VERSION 5.7 ;
  NOWIREEXTENSIONATPIN ON ;
  DIVIDERCHAR "/" ;
  BUSBITCHARS "[]" ;
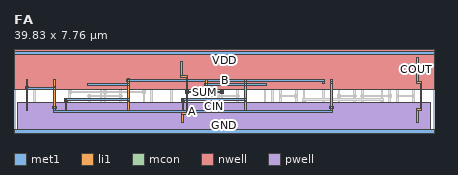
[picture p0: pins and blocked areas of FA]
MACRO FA
  CLASS CORE ;
  FOREIGN FA ;
  ORIGIN 0.000 0.000 ;
  SIZE 39.830 BY 7.760 ;
  SYMMETRY X Y ;
  SITE unitrh ;
  PIN SUM
    DIRECTION OUTPUT ;
    USE SIGNAL ;
    ANTENNADIFFAREA 1.543800 ;
    PORT
      LAYER met1 ;
        RECT 16.285 3.965 16.515 3.995 ;
        RECT 19.615 3.965 19.845 3.995 ;
        RECT 16.255 3.795 19.875 3.965 ;
        RECT 16.285 3.765 16.515 3.795 ;
        RECT 19.615 3.765 19.845 3.795 ;
    END
    PORT
      LAYER li1 ;
        RECT 15.835 5.470 16.005 6.740 ;
        RECT 15.835 5.300 16.485 5.470 ;
        RECT 16.315 1.920 16.485 5.300 ;
        RECT 15.875 1.750 16.485 1.920 ;
        RECT 15.875 1.020 16.045 1.750 ;
      LAYER mcon ;
        RECT 16.315 3.795 16.485 3.965 ;
    END
  END SUM
  PIN COUT
    DIRECTION OUTPUT ;
    USE SIGNAL ;
    ANTENNADIFFAREA 0.771900 ;
    PORT
      LAYER li1 ;
        RECT 38.150 4.845 38.320 7.200 ;
        RECT 38.150 4.675 38.685 4.845 ;
        RECT 38.515 2.345 38.685 4.675 ;
        RECT 38.145 2.175 38.685 2.345 ;
        RECT 38.145 1.020 38.315 2.175 ;
    END
  END COUT
  PIN A
    DIRECTION INPUT ;
    USE SIGNAL ;
    ANTENNAGATEAREA 3.087750 ;
    PORT
      LAYER met1 ;
        RECT 1.115 4.335 1.345 4.365 ;
        RECT 3.705 4.335 3.935 4.365 ;
        RECT 1.085 4.165 3.965 4.335 ;
        RECT 1.115 4.135 1.345 4.165 ;
        RECT 3.705 4.135 3.935 4.165 ;
        RECT 3.735 2.515 3.905 2.545 ;
        RECT 30.005 2.515 30.175 2.545 ;
        RECT 3.705 2.285 3.935 2.515 ;
        RECT 29.975 2.285 30.205 2.515 ;
        RECT 3.735 2.115 3.905 2.285 ;
        RECT 30.005 2.115 30.175 2.285 ;
        RECT 3.735 1.945 30.175 2.115 ;
    END
    PORT
      LAYER li1 ;
        RECT 3.735 2.485 3.905 5.045 ;
        RECT 3.655 2.315 3.985 2.485 ;
        RECT 3.735 2.100 3.905 2.315 ;
      LAYER mcon ;
        RECT 3.735 4.165 3.905 4.335 ;
        RECT 3.735 2.315 3.905 2.485 ;
    END
    PORT
      LAYER li1 ;
        RECT 30.035 4.890 30.205 5.045 ;
        RECT 30.005 4.715 30.205 4.890 ;
        RECT 30.005 2.485 30.175 4.715 ;
        RECT 29.925 2.315 30.255 2.485 ;
        RECT 30.005 2.095 30.175 2.315 ;
      LAYER mcon ;
        RECT 30.005 2.315 30.175 2.485 ;
    END
    PORT
      LAYER li1 ;
        RECT 1.145 2.100 1.315 5.045 ;
      LAYER mcon ;
        RECT 1.145 4.165 1.315 4.335 ;
    END
  END A
  PIN B
    DIRECTION INPUT ;
    USE SIGNAL ;
    ANTENNAGATEAREA 3.087750 ;
    PORT
      LAYER met1 ;
        RECT 10.735 5.075 10.965 5.105 ;
        RECT 10.705 4.925 29.435 5.075 ;
        RECT 10.705 4.905 29.465 4.925 ;
        RECT 10.735 4.875 10.965 4.905 ;
        RECT 7.035 4.705 7.265 4.735 ;
        RECT 10.735 4.705 10.965 4.735 ;
        RECT 7.005 4.535 10.995 4.705 ;
        RECT 29.235 4.695 29.465 4.905 ;
        RECT 29.265 4.665 29.435 4.695 ;
        RECT 7.035 4.505 7.265 4.535 ;
        RECT 10.735 4.505 10.965 4.535 ;
        RECT 4.815 3.225 5.045 3.255 ;
        RECT 10.735 3.225 10.965 3.255 ;
        RECT 4.785 3.055 10.995 3.225 ;
        RECT 4.815 3.025 5.045 3.055 ;
        RECT 10.735 3.025 10.965 3.055 ;
    END
    PORT
      LAYER li1 ;
        RECT 10.765 2.100 10.935 5.155 ;
      LAYER mcon ;
        RECT 10.765 4.905 10.935 5.075 ;
        RECT 10.765 4.535 10.935 4.705 ;
        RECT 10.765 3.055 10.935 3.225 ;
    END
    PORT
      LAYER li1 ;
        RECT 4.845 2.100 5.015 3.305 ;
      LAYER mcon ;
        RECT 4.845 3.055 5.015 3.225 ;
    END
  END B
  PIN CIN
    DIRECTION INPUT ;
    USE SIGNAL ;
    ANTENNAGATEAREA 3.087750 ;
    PORT
      LAYER met1 ;
        RECT 18.135 4.705 18.365 4.735 ;
        RECT 21.835 4.705 22.065 4.735 ;
        RECT 23.685 4.705 23.915 4.735 ;
        RECT 18.105 4.535 23.945 4.705 ;
        RECT 18.135 4.505 18.365 4.535 ;
        RECT 21.835 4.505 22.065 4.535 ;
        RECT 23.685 4.505 23.915 4.535 ;
        RECT 15.915 3.225 16.145 3.255 ;
        RECT 21.835 3.225 22.065 3.255 ;
        RECT 15.885 3.055 22.095 3.225 ;
        RECT 15.915 3.025 16.145 3.055 ;
        RECT 21.835 3.025 22.065 3.055 ;
    END
    PORT
      LAYER li1 ;
        RECT 21.865 2.100 22.035 5.045 ;
      LAYER mcon ;
        RECT 21.865 4.535 22.035 4.705 ;
        RECT 21.865 3.055 22.035 3.225 ;
    END
    PORT
      LAYER li1 ;
        RECT 18.165 4.455 18.335 5.045 ;
      LAYER mcon ;
        RECT 18.165 4.535 18.335 4.705 ;
    END
    PORT
      LAYER li1 ;
        RECT 15.945 2.100 16.115 3.305 ;
      LAYER mcon ;
        RECT 15.945 3.055 16.115 3.225 ;
    END
  END CIN
  PIN VDD
    DIRECTION INOUT ;
    USE POWER ;
    SHAPE ABUTMENT ;
    PORT
      LAYER nwell ;
        RECT 0.000 4.110 39.830 7.940 ;
      LAYER met1 ;
        RECT 0.000 7.410 39.830 7.760 ;
    END
  END VDD
  PIN GND
    DIRECTION INOUT ;
    USE GROUND ;
    SHAPE ABUTMENT ;
    PORT
      LAYER pwell ;
        RECT 0.320 0.000 39.510 2.900 ;
      LAYER met1 ;
        RECT 0.000 0.000 39.830 0.350 ;
    END
  END GND
  OBS
      LAYER li1 ;
        RECT 0.000 7.410 39.830 7.760 ;
        RECT 0.320 4.290 0.660 7.410 ;
        RECT 1.080 5.365 1.250 7.410 ;
        RECT 1.520 4.845 1.690 7.200 ;
        RECT 1.960 5.365 2.130 7.410 ;
        RECT 1.520 4.675 2.055 4.845 ;
        RECT 0.320 0.350 0.660 2.900 ;
        RECT 1.885 2.345 2.055 4.675 ;
        RECT 2.540 4.290 2.880 7.410 ;
        RECT 3.415 5.470 3.585 7.080 ;
        RECT 3.855 5.730 4.025 7.410 ;
        RECT 4.295 7.000 5.345 7.170 ;
        RECT 4.295 5.470 4.465 7.000 ;
        RECT 3.415 5.300 4.465 5.470 ;
        RECT 4.735 5.470 4.905 6.740 ;
        RECT 5.175 5.730 5.345 7.000 ;
        RECT 4.735 5.300 5.385 5.470 ;
        RECT 4.845 4.085 5.015 5.045 ;
        RECT 1.515 2.175 2.055 2.345 ;
        RECT 1.035 0.800 1.205 1.930 ;
        RECT 1.515 1.020 1.685 2.175 ;
        RECT 2.005 0.800 2.175 1.930 ;
        RECT 1.035 0.630 2.175 0.800 ;
        RECT 1.035 0.350 1.205 0.630 ;
        RECT 1.520 0.350 1.690 0.630 ;
        RECT 2.005 0.350 2.175 0.630 ;
        RECT 2.540 0.350 2.880 2.900 ;
        RECT 3.320 1.850 3.490 1.930 ;
        RECT 4.290 1.850 4.460 1.930 ;
        RECT 5.215 1.920 5.385 5.300 ;
        RECT 5.870 4.290 6.210 7.410 ;
        RECT 6.745 5.470 6.915 7.080 ;
        RECT 7.185 5.730 7.355 7.410 ;
        RECT 7.625 7.000 8.675 7.170 ;
        RECT 7.625 5.470 7.795 7.000 ;
        RECT 6.745 5.300 7.795 5.470 ;
        RECT 8.065 5.470 8.235 6.740 ;
        RECT 8.505 5.730 8.675 7.000 ;
        RECT 8.065 5.300 8.715 5.470 ;
        RECT 7.065 4.455 7.235 5.045 ;
        RECT 3.320 1.680 4.460 1.850 ;
        RECT 3.320 0.550 3.490 1.680 ;
        RECT 3.805 0.350 3.975 1.305 ;
        RECT 4.290 0.800 4.460 1.680 ;
        RECT 4.775 1.750 5.385 1.920 ;
        RECT 4.775 1.020 4.945 1.750 ;
        RECT 5.260 0.800 5.430 1.570 ;
        RECT 4.290 0.630 5.430 0.800 ;
        RECT 4.290 0.550 4.460 0.630 ;
        RECT 5.260 0.550 5.430 0.630 ;
        RECT 5.870 0.350 6.210 2.900 ;
        RECT 7.065 2.100 7.235 3.675 ;
        RECT 8.175 2.100 8.345 5.045 ;
        RECT 6.650 1.850 6.820 1.930 ;
        RECT 7.620 1.850 7.790 1.930 ;
        RECT 8.545 1.920 8.715 5.300 ;
        RECT 9.200 4.290 9.540 7.410 ;
        RECT 9.950 5.365 10.120 7.410 ;
        RECT 10.390 4.845 10.560 7.200 ;
        RECT 10.830 5.365 11.000 7.410 ;
        RECT 10.025 4.675 10.560 4.845 ;
        RECT 6.650 1.680 7.790 1.850 ;
        RECT 6.650 0.550 6.820 1.680 ;
        RECT 7.135 0.350 7.305 1.305 ;
        RECT 7.620 0.800 7.790 1.680 ;
        RECT 8.105 1.750 8.715 1.920 ;
        RECT 8.105 1.020 8.275 1.750 ;
        RECT 8.590 0.800 8.760 1.570 ;
        RECT 7.620 0.630 8.760 0.800 ;
        RECT 7.620 0.550 7.790 0.630 ;
        RECT 8.590 0.550 8.760 0.630 ;
        RECT 9.200 0.350 9.540 2.900 ;
        RECT 10.025 2.345 10.195 4.675 ;
        RECT 11.420 4.290 11.760 7.410 ;
        RECT 12.180 5.365 12.350 7.410 ;
        RECT 10.025 2.175 10.565 2.345 ;
        RECT 9.905 0.800 10.075 1.930 ;
        RECT 10.395 1.020 10.565 2.175 ;
        RECT 10.875 0.800 11.045 1.930 ;
        RECT 9.905 0.630 11.045 0.800 ;
        RECT 9.905 0.350 10.075 0.630 ;
        RECT 10.390 0.350 10.560 0.630 ;
        RECT 10.875 0.350 11.045 0.630 ;
        RECT 11.420 0.350 11.760 2.900 ;
        RECT 12.245 2.100 12.415 5.045 ;
        RECT 12.620 4.845 12.790 7.200 ;
        RECT 13.060 5.365 13.230 7.410 ;
        RECT 12.620 4.675 13.155 4.845 ;
        RECT 12.985 2.345 13.155 4.675 ;
        RECT 13.640 4.290 13.980 7.410 ;
        RECT 14.515 5.470 14.685 7.080 ;
        RECT 14.955 5.730 15.125 7.410 ;
        RECT 15.395 7.000 16.445 7.170 ;
        RECT 15.395 5.470 15.565 7.000 ;
        RECT 16.275 5.730 16.445 7.000 ;
        RECT 14.515 5.300 15.565 5.470 ;
        RECT 12.615 2.175 13.155 2.345 ;
        RECT 12.135 0.800 12.305 1.930 ;
        RECT 12.615 1.020 12.785 2.175 ;
        RECT 13.105 0.800 13.275 1.930 ;
        RECT 12.135 0.630 13.275 0.800 ;
        RECT 12.135 0.350 12.305 0.630 ;
        RECT 12.620 0.350 12.790 0.630 ;
        RECT 13.105 0.350 13.275 0.630 ;
        RECT 13.640 0.350 13.980 2.900 ;
        RECT 14.835 2.100 15.005 5.045 ;
        RECT 15.945 4.085 16.115 5.045 ;
        RECT 16.970 4.290 17.310 7.410 ;
        RECT 17.845 5.470 18.015 7.080 ;
        RECT 18.285 5.730 18.455 7.410 ;
        RECT 18.725 7.000 19.775 7.170 ;
        RECT 18.725 5.470 18.895 7.000 ;
        RECT 17.845 5.300 18.895 5.470 ;
        RECT 19.165 5.470 19.335 6.740 ;
        RECT 19.605 5.730 19.775 7.000 ;
        RECT 19.165 5.300 19.815 5.470 ;
        RECT 14.420 1.850 14.590 1.930 ;
        RECT 15.390 1.850 15.560 1.930 ;
        RECT 14.420 1.680 15.560 1.850 ;
        RECT 14.420 0.550 14.590 1.680 ;
        RECT 14.905 0.350 15.075 1.305 ;
        RECT 15.390 0.800 15.560 1.680 ;
        RECT 16.360 0.800 16.530 1.570 ;
        RECT 15.390 0.630 16.530 0.800 ;
        RECT 15.390 0.550 15.560 0.630 ;
        RECT 16.360 0.550 16.530 0.630 ;
        RECT 16.970 0.350 17.310 2.900 ;
        RECT 18.165 2.100 18.335 3.675 ;
        RECT 19.275 2.100 19.445 5.045 ;
        RECT 17.750 1.850 17.920 1.930 ;
        RECT 18.720 1.850 18.890 1.930 ;
        RECT 19.645 1.920 19.815 5.300 ;
        RECT 20.300 4.290 20.640 7.410 ;
        RECT 21.050 5.365 21.220 7.410 ;
        RECT 21.490 4.845 21.660 7.200 ;
        RECT 21.930 5.365 22.100 7.410 ;
        RECT 21.125 4.675 21.660 4.845 ;
        RECT 17.750 1.680 18.890 1.850 ;
        RECT 17.750 0.550 17.920 1.680 ;
        RECT 18.235 0.350 18.405 1.305 ;
        RECT 18.720 0.800 18.890 1.680 ;
        RECT 19.205 1.750 19.815 1.920 ;
        RECT 19.205 1.020 19.375 1.750 ;
        RECT 19.690 0.800 19.860 1.570 ;
        RECT 18.720 0.630 19.860 0.800 ;
        RECT 18.720 0.550 18.890 0.630 ;
        RECT 19.690 0.550 19.860 0.630 ;
        RECT 20.300 0.350 20.640 2.900 ;
        RECT 21.125 2.345 21.295 4.675 ;
        RECT 22.520 4.290 22.860 7.410 ;
        RECT 23.395 5.315 23.565 7.410 ;
        RECT 23.835 5.465 24.005 7.200 ;
        RECT 24.275 5.735 24.445 7.410 ;
        RECT 24.715 5.465 24.885 7.200 ;
        RECT 25.155 5.735 25.325 7.410 ;
        RECT 23.835 5.295 25.365 5.465 ;
        RECT 21.125 2.175 21.665 2.345 ;
        RECT 21.005 0.800 21.175 1.930 ;
        RECT 21.495 1.020 21.665 2.175 ;
        RECT 21.975 0.800 22.145 1.930 ;
        RECT 21.005 0.630 22.145 0.800 ;
        RECT 21.005 0.350 21.175 0.630 ;
        RECT 21.490 0.350 21.660 0.630 ;
        RECT 21.975 0.350 22.145 0.630 ;
        RECT 22.520 0.350 22.860 2.900 ;
        RECT 23.715 2.095 23.885 5.045 ;
        RECT 24.485 4.890 24.655 5.045 ;
        RECT 24.455 4.715 24.655 4.890 ;
        RECT 24.455 2.095 24.625 4.715 ;
        RECT 23.300 1.845 23.470 1.925 ;
        RECT 24.270 1.845 24.440 1.925 ;
        RECT 25.195 1.920 25.365 5.295 ;
        RECT 25.850 4.290 26.190 7.410 ;
        RECT 26.610 5.365 26.780 7.410 ;
        RECT 23.300 1.675 24.440 1.845 ;
        RECT 23.300 0.545 23.470 1.675 ;
        RECT 23.785 0.350 23.955 1.300 ;
        RECT 24.270 0.795 24.440 1.675 ;
        RECT 24.755 1.750 25.365 1.920 ;
        RECT 24.755 1.015 24.925 1.750 ;
        RECT 25.240 0.795 25.410 1.565 ;
        RECT 24.270 0.625 25.410 0.795 ;
        RECT 24.270 0.545 24.440 0.625 ;
        RECT 25.240 0.545 25.410 0.625 ;
        RECT 25.850 0.350 26.190 2.900 ;
        RECT 26.675 2.100 26.845 5.045 ;
        RECT 27.050 4.845 27.220 7.200 ;
        RECT 27.490 5.365 27.660 7.410 ;
        RECT 27.050 4.675 27.585 4.845 ;
        RECT 27.415 2.345 27.585 4.675 ;
        RECT 28.070 4.290 28.410 7.410 ;
        RECT 28.945 5.315 29.115 7.410 ;
        RECT 29.385 5.465 29.555 7.200 ;
        RECT 29.825 5.735 29.995 7.410 ;
        RECT 30.265 5.465 30.435 7.200 ;
        RECT 30.705 5.735 30.875 7.410 ;
        RECT 29.385 5.295 30.915 5.465 ;
        RECT 29.265 4.895 29.435 5.075 ;
        RECT 29.185 4.725 29.515 4.895 ;
        RECT 27.045 2.175 27.585 2.345 ;
        RECT 26.565 0.800 26.735 1.930 ;
        RECT 27.045 1.020 27.215 2.175 ;
        RECT 27.535 0.800 27.705 1.930 ;
        RECT 26.565 0.630 27.705 0.800 ;
        RECT 26.565 0.350 26.735 0.630 ;
        RECT 27.050 0.350 27.220 0.630 ;
        RECT 27.535 0.350 27.705 0.630 ;
        RECT 28.070 0.350 28.410 2.900 ;
        RECT 29.265 2.095 29.435 4.725 ;
        RECT 28.850 1.845 29.020 1.925 ;
        RECT 29.820 1.845 29.990 1.925 ;
        RECT 30.745 1.920 30.915 5.295 ;
        RECT 31.400 4.290 31.740 7.410 ;
        RECT 32.160 5.365 32.330 7.410 ;
        RECT 28.850 1.675 29.990 1.845 ;
        RECT 28.850 0.545 29.020 1.675 ;
        RECT 29.335 0.350 29.505 1.300 ;
        RECT 29.820 0.795 29.990 1.675 ;
        RECT 30.305 1.750 30.915 1.920 ;
        RECT 30.305 1.015 30.475 1.750 ;
        RECT 30.790 0.795 30.960 1.565 ;
        RECT 29.820 0.625 30.960 0.795 ;
        RECT 29.820 0.545 29.990 0.625 ;
        RECT 30.790 0.545 30.960 0.625 ;
        RECT 31.400 0.350 31.740 2.900 ;
        RECT 32.225 2.100 32.395 5.045 ;
        RECT 32.600 4.845 32.770 7.200 ;
        RECT 33.040 5.365 33.210 7.410 ;
        RECT 32.600 4.675 33.135 4.845 ;
        RECT 32.965 2.345 33.135 4.675 ;
        RECT 33.620 4.290 33.960 7.410 ;
        RECT 34.495 5.475 34.665 7.205 ;
        RECT 34.935 5.735 35.105 7.410 ;
        RECT 35.375 7.005 36.425 7.175 ;
        RECT 35.375 5.475 35.545 7.005 ;
        RECT 34.495 5.305 35.545 5.475 ;
        RECT 35.815 5.475 35.985 6.745 ;
        RECT 36.255 5.735 36.425 7.005 ;
        RECT 35.815 5.305 36.465 5.475 ;
        RECT 34.660 4.890 34.830 5.050 ;
        RECT 35.590 4.890 35.760 5.050 ;
        RECT 34.660 4.720 34.985 4.890 ;
        RECT 32.595 2.175 33.135 2.345 ;
        RECT 32.115 0.800 32.285 1.930 ;
        RECT 32.595 1.020 32.765 2.175 ;
        RECT 33.085 0.800 33.255 1.930 ;
        RECT 32.115 0.630 33.255 0.800 ;
        RECT 32.115 0.350 32.285 0.630 ;
        RECT 32.600 0.350 32.770 0.630 ;
        RECT 33.085 0.350 33.255 0.630 ;
        RECT 33.620 0.350 33.960 2.900 ;
        RECT 34.815 2.095 34.985 4.720 ;
        RECT 35.555 4.720 35.760 4.890 ;
        RECT 35.555 2.095 35.725 4.720 ;
        RECT 34.400 0.795 34.570 1.925 ;
        RECT 36.295 1.920 36.465 5.305 ;
        RECT 36.950 4.290 37.290 7.410 ;
        RECT 37.710 5.365 37.880 7.410 ;
        RECT 38.590 5.365 38.760 7.410 ;
        RECT 34.885 1.750 36.465 1.920 ;
        RECT 34.885 1.015 35.055 1.750 ;
        RECT 35.370 0.795 35.540 1.570 ;
        RECT 35.855 1.015 36.025 1.750 ;
        RECT 36.340 0.795 36.510 1.570 ;
        RECT 34.400 0.625 36.510 0.795 ;
        RECT 34.400 0.350 34.570 0.625 ;
        RECT 34.885 0.350 35.055 0.625 ;
        RECT 35.370 0.350 35.540 0.625 ;
        RECT 35.855 0.350 36.025 0.625 ;
        RECT 36.340 0.350 36.510 0.625 ;
        RECT 36.950 0.350 37.290 2.900 ;
        RECT 37.775 2.100 37.945 5.045 ;
        RECT 39.170 4.290 39.510 7.410 ;
        RECT 37.665 0.800 37.835 1.930 ;
        RECT 38.635 0.800 38.805 1.930 ;
        RECT 37.665 0.630 38.805 0.800 ;
        RECT 37.665 0.350 37.835 0.630 ;
        RECT 38.150 0.350 38.320 0.630 ;
        RECT 38.635 0.350 38.805 0.630 ;
        RECT 39.170 0.350 39.510 2.900 ;
        RECT 0.000 0.000 39.830 0.350 ;
      LAYER mcon ;
        RECT 0.775 7.495 0.945 7.665 ;
        RECT 1.145 7.495 1.315 7.665 ;
        RECT 1.515 7.495 1.685 7.665 ;
        RECT 1.885 7.495 2.055 7.665 ;
        RECT 2.255 7.495 2.425 7.665 ;
        RECT 2.995 7.495 3.165 7.665 ;
        RECT 3.365 7.495 3.535 7.665 ;
        RECT 3.735 7.495 3.905 7.665 ;
        RECT 4.105 7.495 4.275 7.665 ;
        RECT 4.475 7.495 4.645 7.665 ;
        RECT 4.845 7.495 5.015 7.665 ;
        RECT 5.215 7.495 5.385 7.665 ;
        RECT 5.585 7.495 5.755 7.665 ;
        RECT 6.325 7.495 6.495 7.665 ;
        RECT 6.695 7.495 6.865 7.665 ;
        RECT 7.065 7.495 7.235 7.665 ;
        RECT 7.435 7.495 7.605 7.665 ;
        RECT 7.805 7.495 7.975 7.665 ;
        RECT 8.175 7.495 8.345 7.665 ;
        RECT 8.545 7.495 8.715 7.665 ;
        RECT 8.915 7.495 9.085 7.665 ;
        RECT 9.655 7.495 9.825 7.665 ;
        RECT 10.025 7.495 10.195 7.665 ;
        RECT 10.395 7.495 10.565 7.665 ;
        RECT 10.765 7.495 10.935 7.665 ;
        RECT 11.135 7.495 11.305 7.665 ;
        RECT 11.875 7.495 12.045 7.665 ;
        RECT 12.245 7.495 12.415 7.665 ;
        RECT 12.615 7.495 12.785 7.665 ;
        RECT 12.985 7.495 13.155 7.665 ;
        RECT 13.355 7.495 13.525 7.665 ;
        RECT 14.095 7.495 14.265 7.665 ;
        RECT 14.465 7.495 14.635 7.665 ;
        RECT 14.835 7.495 15.005 7.665 ;
        RECT 15.205 7.495 15.375 7.665 ;
        RECT 15.575 7.495 15.745 7.665 ;
        RECT 15.945 7.495 16.115 7.665 ;
        RECT 16.315 7.495 16.485 7.665 ;
        RECT 16.685 7.495 16.855 7.665 ;
        RECT 17.425 7.495 17.595 7.665 ;
        RECT 17.795 7.495 17.965 7.665 ;
        RECT 18.165 7.495 18.335 7.665 ;
        RECT 18.535 7.495 18.705 7.665 ;
        RECT 18.905 7.495 19.075 7.665 ;
        RECT 19.275 7.495 19.445 7.665 ;
        RECT 19.645 7.495 19.815 7.665 ;
        RECT 20.015 7.495 20.185 7.665 ;
        RECT 20.755 7.495 20.925 7.665 ;
        RECT 21.125 7.495 21.295 7.665 ;
        RECT 21.495 7.495 21.665 7.665 ;
        RECT 21.865 7.495 22.035 7.665 ;
        RECT 22.235 7.495 22.405 7.665 ;
        RECT 22.975 7.495 23.145 7.665 ;
        RECT 23.345 7.495 23.515 7.665 ;
        RECT 23.715 7.495 23.885 7.665 ;
        RECT 24.085 7.495 24.255 7.665 ;
        RECT 24.455 7.495 24.625 7.665 ;
        RECT 24.825 7.495 24.995 7.665 ;
        RECT 25.195 7.495 25.365 7.665 ;
        RECT 25.565 7.495 25.735 7.665 ;
        RECT 26.305 7.495 26.475 7.665 ;
        RECT 26.675 7.495 26.845 7.665 ;
        RECT 27.045 7.495 27.215 7.665 ;
        RECT 27.415 7.495 27.585 7.665 ;
        RECT 27.785 7.495 27.955 7.665 ;
        RECT 28.525 7.495 28.695 7.665 ;
        RECT 28.895 7.495 29.065 7.665 ;
        RECT 29.265 7.495 29.435 7.665 ;
        RECT 29.635 7.495 29.805 7.665 ;
        RECT 30.005 7.495 30.175 7.665 ;
        RECT 30.375 7.495 30.545 7.665 ;
        RECT 30.745 7.495 30.915 7.665 ;
        RECT 31.115 7.495 31.285 7.665 ;
        RECT 31.855 7.495 32.025 7.665 ;
        RECT 32.225 7.495 32.395 7.665 ;
        RECT 32.595 7.495 32.765 7.665 ;
        RECT 32.965 7.495 33.135 7.665 ;
        RECT 33.335 7.495 33.505 7.665 ;
        RECT 34.075 7.495 34.245 7.665 ;
        RECT 34.445 7.495 34.615 7.665 ;
        RECT 34.815 7.495 34.985 7.665 ;
        RECT 35.185 7.495 35.355 7.665 ;
        RECT 35.555 7.495 35.725 7.665 ;
        RECT 35.925 7.495 36.095 7.665 ;
        RECT 36.295 7.495 36.465 7.665 ;
        RECT 36.665 7.495 36.835 7.665 ;
        RECT 37.405 7.495 37.575 7.665 ;
        RECT 37.775 7.495 37.945 7.665 ;
        RECT 38.145 7.495 38.315 7.665 ;
        RECT 38.515 7.495 38.685 7.665 ;
        RECT 38.885 7.495 39.055 7.665 ;
        RECT 4.845 4.165 5.015 4.335 ;
        RECT 7.065 4.535 7.235 4.705 ;
        RECT 5.215 3.795 5.385 3.965 ;
        RECT 1.885 2.685 2.055 2.855 ;
        RECT 7.065 3.425 7.235 3.595 ;
        RECT 8.175 2.685 8.345 2.855 ;
        RECT 8.545 3.795 8.715 3.965 ;
        RECT 10.025 4.165 10.195 4.335 ;
        RECT 10.025 3.425 10.195 3.595 ;
        RECT 12.245 4.165 12.415 4.335 ;
        RECT 12.245 3.795 12.415 3.965 ;
        RECT 12.245 2.315 12.415 2.485 ;
        RECT 14.835 4.165 15.005 4.335 ;
        RECT 12.985 2.685 13.155 2.855 ;
        RECT 15.945 4.165 16.115 4.335 ;
        RECT 18.165 3.425 18.335 3.595 ;
        RECT 19.275 2.685 19.445 2.855 ;
        RECT 19.645 3.795 19.815 3.965 ;
        RECT 21.125 4.165 21.295 4.335 ;
        RECT 23.715 4.535 23.885 4.705 ;
        RECT 21.125 3.425 21.295 3.595 ;
        RECT 24.455 2.315 24.625 2.485 ;
        RECT 25.195 3.425 25.365 3.595 ;
        RECT 26.675 3.425 26.845 3.595 ;
        RECT 29.265 4.725 29.435 4.895 ;
        RECT 27.415 3.055 27.585 3.225 ;
        RECT 30.745 3.425 30.915 3.595 ;
        RECT 32.225 3.425 32.395 3.595 ;
        RECT 32.965 3.425 33.135 3.595 ;
        RECT 34.815 3.055 34.985 3.225 ;
        RECT 35.555 3.425 35.725 3.595 ;
        RECT 36.295 3.425 36.465 3.595 ;
        RECT 37.775 3.425 37.945 3.595 ;
        RECT 0.775 0.095 0.945 0.265 ;
        RECT 1.145 0.095 1.315 0.265 ;
        RECT 1.515 0.095 1.685 0.265 ;
        RECT 1.885 0.095 2.055 0.265 ;
        RECT 2.255 0.095 2.425 0.265 ;
        RECT 2.995 0.095 3.165 0.265 ;
        RECT 3.365 0.095 3.535 0.265 ;
        RECT 3.735 0.095 3.905 0.265 ;
        RECT 4.105 0.095 4.275 0.265 ;
        RECT 4.475 0.095 4.645 0.265 ;
        RECT 4.845 0.095 5.015 0.265 ;
        RECT 5.215 0.095 5.385 0.265 ;
        RECT 5.585 0.095 5.755 0.265 ;
        RECT 6.325 0.095 6.495 0.265 ;
        RECT 6.695 0.095 6.865 0.265 ;
        RECT 7.065 0.095 7.235 0.265 ;
        RECT 7.435 0.095 7.605 0.265 ;
        RECT 7.805 0.095 7.975 0.265 ;
        RECT 8.175 0.095 8.345 0.265 ;
        RECT 8.545 0.095 8.715 0.265 ;
        RECT 8.915 0.095 9.085 0.265 ;
        RECT 9.655 0.095 9.825 0.265 ;
        RECT 10.025 0.095 10.195 0.265 ;
        RECT 10.395 0.095 10.565 0.265 ;
        RECT 10.765 0.095 10.935 0.265 ;
        RECT 11.135 0.095 11.305 0.265 ;
        RECT 11.875 0.095 12.045 0.265 ;
        RECT 12.245 0.095 12.415 0.265 ;
        RECT 12.615 0.095 12.785 0.265 ;
        RECT 12.985 0.095 13.155 0.265 ;
        RECT 13.355 0.095 13.525 0.265 ;
        RECT 14.095 0.095 14.265 0.265 ;
        RECT 14.465 0.095 14.635 0.265 ;
        RECT 14.835 0.095 15.005 0.265 ;
        RECT 15.205 0.095 15.375 0.265 ;
        RECT 15.575 0.095 15.745 0.265 ;
        RECT 15.945 0.095 16.115 0.265 ;
        RECT 16.315 0.095 16.485 0.265 ;
        RECT 16.685 0.095 16.855 0.265 ;
        RECT 17.425 0.095 17.595 0.265 ;
        RECT 17.795 0.095 17.965 0.265 ;
        RECT 18.165 0.095 18.335 0.265 ;
        RECT 18.535 0.095 18.705 0.265 ;
        RECT 18.905 0.095 19.075 0.265 ;
        RECT 19.275 0.095 19.445 0.265 ;
        RECT 19.645 0.095 19.815 0.265 ;
        RECT 20.015 0.095 20.185 0.265 ;
        RECT 20.755 0.095 20.925 0.265 ;
        RECT 21.125 0.095 21.295 0.265 ;
        RECT 21.495 0.095 21.665 0.265 ;
        RECT 21.865 0.095 22.035 0.265 ;
        RECT 22.235 0.095 22.405 0.265 ;
        RECT 22.975 0.095 23.145 0.265 ;
        RECT 23.345 0.095 23.515 0.265 ;
        RECT 23.715 0.095 23.885 0.265 ;
        RECT 24.085 0.095 24.255 0.265 ;
        RECT 24.455 0.095 24.625 0.265 ;
        RECT 24.825 0.095 24.995 0.265 ;
        RECT 25.195 0.095 25.365 0.265 ;
        RECT 25.565 0.095 25.735 0.265 ;
        RECT 26.305 0.095 26.475 0.265 ;
        RECT 26.675 0.095 26.845 0.265 ;
        RECT 27.045 0.095 27.215 0.265 ;
        RECT 27.415 0.095 27.585 0.265 ;
        RECT 27.785 0.095 27.955 0.265 ;
        RECT 28.525 0.095 28.695 0.265 ;
        RECT 28.895 0.095 29.065 0.265 ;
        RECT 29.265 0.095 29.435 0.265 ;
        RECT 29.635 0.095 29.805 0.265 ;
        RECT 30.005 0.095 30.175 0.265 ;
        RECT 30.375 0.095 30.545 0.265 ;
        RECT 30.745 0.095 30.915 0.265 ;
        RECT 31.115 0.095 31.285 0.265 ;
        RECT 31.855 0.095 32.025 0.265 ;
        RECT 32.225 0.095 32.395 0.265 ;
        RECT 32.595 0.095 32.765 0.265 ;
        RECT 32.965 0.095 33.135 0.265 ;
        RECT 33.335 0.095 33.505 0.265 ;
        RECT 34.075 0.095 34.245 0.265 ;
        RECT 34.445 0.095 34.615 0.265 ;
        RECT 34.815 0.095 34.985 0.265 ;
        RECT 35.185 0.095 35.355 0.265 ;
        RECT 35.555 0.095 35.725 0.265 ;
        RECT 35.925 0.095 36.095 0.265 ;
        RECT 36.295 0.095 36.465 0.265 ;
        RECT 36.665 0.095 36.835 0.265 ;
        RECT 37.405 0.095 37.575 0.265 ;
        RECT 37.775 0.095 37.945 0.265 ;
        RECT 38.145 0.095 38.315 0.265 ;
        RECT 38.515 0.095 38.685 0.265 ;
        RECT 38.885 0.095 39.055 0.265 ;
      LAYER met1 ;
        RECT 4.815 4.335 5.045 4.365 ;
        RECT 9.995 4.335 10.225 4.365 ;
        RECT 12.215 4.335 12.445 4.365 ;
        RECT 14.805 4.335 15.035 4.365 ;
        RECT 15.915 4.335 16.145 4.365 ;
        RECT 21.095 4.335 21.325 4.365 ;
        RECT 4.785 4.165 10.255 4.335 ;
        RECT 12.185 4.165 15.065 4.335 ;
        RECT 15.885 4.165 21.355 4.335 ;
        RECT 4.815 4.135 5.045 4.165 ;
        RECT 9.995 4.135 10.225 4.165 ;
        RECT 12.215 4.135 12.445 4.165 ;
        RECT 14.805 4.135 15.035 4.165 ;
        RECT 15.915 4.135 16.145 4.165 ;
        RECT 21.095 4.135 21.325 4.165 ;
        RECT 5.185 3.965 5.415 3.995 ;
        RECT 8.515 3.965 8.745 3.995 ;
        RECT 12.215 3.965 12.445 3.995 ;
        RECT 5.155 3.795 12.475 3.965 ;
        RECT 5.185 3.765 5.415 3.795 ;
        RECT 8.515 3.765 8.745 3.795 ;
        RECT 12.215 3.765 12.445 3.795 ;
        RECT 7.035 3.595 7.265 3.625 ;
        RECT 9.995 3.595 10.225 3.625 ;
        RECT 18.135 3.595 18.365 3.625 ;
        RECT 21.095 3.595 21.325 3.625 ;
        RECT 25.165 3.595 25.395 3.625 ;
        RECT 26.645 3.595 26.875 3.625 ;
        RECT 30.715 3.595 30.945 3.625 ;
        RECT 32.195 3.595 32.425 3.625 ;
        RECT 32.935 3.595 33.165 3.625 ;
        RECT 35.525 3.595 35.755 3.625 ;
        RECT 36.265 3.595 36.495 3.625 ;
        RECT 37.745 3.595 37.975 3.625 ;
        RECT 7.005 3.425 10.255 3.595 ;
        RECT 18.105 3.425 21.355 3.595 ;
        RECT 25.135 3.425 26.905 3.595 ;
        RECT 30.685 3.425 32.455 3.595 ;
        RECT 32.905 3.425 35.785 3.595 ;
        RECT 36.235 3.425 38.005 3.595 ;
        RECT 7.035 3.395 7.265 3.425 ;
        RECT 9.995 3.395 10.225 3.425 ;
        RECT 18.135 3.395 18.365 3.425 ;
        RECT 21.095 3.395 21.325 3.425 ;
        RECT 25.165 3.395 25.395 3.425 ;
        RECT 26.645 3.395 26.875 3.425 ;
        RECT 30.715 3.395 30.945 3.425 ;
        RECT 32.195 3.395 32.425 3.425 ;
        RECT 32.935 3.395 33.165 3.425 ;
        RECT 35.525 3.395 35.755 3.425 ;
        RECT 36.265 3.395 36.495 3.425 ;
        RECT 37.745 3.395 37.975 3.425 ;
        RECT 27.385 3.225 27.615 3.255 ;
        RECT 34.785 3.225 35.015 3.255 ;
        RECT 27.355 3.055 35.045 3.225 ;
        RECT 27.385 3.025 27.615 3.055 ;
        RECT 34.785 3.025 35.015 3.055 ;
        RECT 1.855 2.855 2.085 2.885 ;
        RECT 8.145 2.855 8.375 2.885 ;
        RECT 12.955 2.855 13.185 2.885 ;
        RECT 19.245 2.855 19.475 2.885 ;
        RECT 1.825 2.685 8.405 2.855 ;
        RECT 12.925 2.685 19.505 2.855 ;
        RECT 1.855 2.655 2.085 2.685 ;
        RECT 8.145 2.655 8.375 2.685 ;
        RECT 12.955 2.655 13.185 2.685 ;
        RECT 19.245 2.655 19.475 2.685 ;
        RECT 12.215 2.485 12.445 2.515 ;
        RECT 24.425 2.485 24.655 2.515 ;
        RECT 12.185 2.315 24.685 2.485 ;
        RECT 12.215 2.285 12.445 2.315 ;
        RECT 24.425 2.285 24.655 2.315 ;
  END
END FA
END LIBRARY

